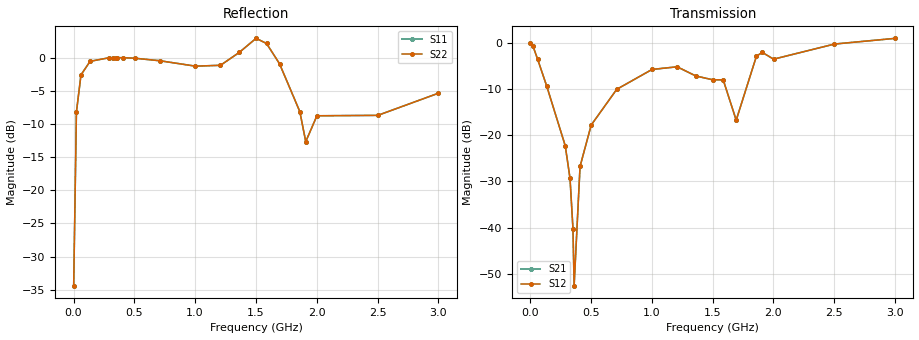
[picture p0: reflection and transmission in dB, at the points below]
!s-Parameter Generated by FASTRON Sdn. Bhd.
!FASTRON P/N : MICC-R33X
!Keysight Technologies,E4991B,MY54100416,A.01.15
!Date: Fri Aug 21 14:26:19 2026
!Version  : Rev00 Fri Aug 21 14:26:19 2026
!Data & Calibration Information:
!PortZ  Port1:50+j0  Port2:50+j0
!When reading, reference impedance value at option line is always used.
! Remarks : This data is being provided solely for informational purposes.
!Freq	S11	S21	S12	S22
# Hz S dB R 50
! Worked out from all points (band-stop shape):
!   1601 points, 1 MHz to 3 GHz, reference 50 ohm
!   highest |S21| = 0.95 dB at 3 GHz (marker M1); lowest = -52.5 dB at 360.9 MHz (marker M2)
!   |S21| within 3 dB of the highest: start of sweep to 41.84 MHz; 2.201 GHz to end of sweep (the widest 2 of 3)
!   lowest |S11| = -34.4 dB at 1 MHz (marker M3), VSWR 1.04, Z = 50.2 + j1.9 ohm
!   |S11| at or under -10 dB: start of sweep to 18.59 MHz; 1.878 GHz to 1.95 GHz (72 MHz wide, 3.76 % of centre)
!   |S22| runs from -34.4 to 2.9 dB; largest |S21 - S12| = 0
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1000000  -34.40 83.5  -0.02 -1.1  -0.02 -1.1  -34.40 83.5
2.34925e7  -8.23 65.9  -0.79 -22.8  -0.79 -22.8  -8.23 65.9
6.098e7  -2.62 41.4  -3.58 -47.7  -3.58 -47.7  -2.62 41.4
1.35955e8  -0.57 19.8  -9.40 -69.5  -9.40 -69.5  -0.57 19.8
2.877794e8  -0.05 4.4  -22.26 -83.8  -22.26 -83.8  -0.05 4.4
3.271412e8  -0.03 2.0  -29.30 -84.0  -29.30 -84.0  -0.03 2.0
3.515081e8  -0.02 0.5  -40.29 -75.8  -40.29 -75.8  -0.02 0.5
3.6088e8  -0.02 0.0  -52.54 -3.1  -52.54 -3.1  -0.02 0.0
4.096138e8  -0.03 -2.6  -26.75 84.4  -26.75 84.4  -0.03 -2.6
5.014581e8  -0.10 -7.4  -17.79 81.3  -17.79 81.3  -0.10 -7.4
7.113881e8  -0.49 -18.3  -10.07 70.9  -10.07 70.9  -0.49 -18.3
1.001916e9  -1.30 -31.0  -5.77 59.4  -5.77 59.4  -1.30 -31.0
1.208098e9  -1.17 -33.3  -5.20 60.7  -5.20 60.7  -1.17 -33.3
1.361796e9  0.76 -23.7  -7.18 89.9  -7.18 89.9  0.76 -23.7
1.5005e9  2.89 2.5  -8.01 -171.1  -8.01 -171.1  2.89 2.5
1.586721e9  2.12 14.5  -8.02 -126.3  -8.02 -126.3  2.12 14.5
1.693561e9  -0.94 6.2  -16.75 -42.0  -16.75 -42.0  -0.94 6.2
1.86038e9  -8.15 -35.5  -2.87 18.4  -2.87 18.4  -8.15 -35.5
1.909114e9  -12.68 -19.7  -2.10 5.7  -2.10 5.7  -12.68 -19.7
2.000958e9  -8.78 -18.4  -3.55 9.9  -3.55 9.9  -8.78 -18.4
2.501416e9  -8.72 -74.4  -0.28 21.4  -0.28 21.4  -8.72 -74.4
3e9  -5.38 -87.6  0.95 28.8  0.95 28.8  -5.38 -87.6
